VERSION 5.7 ;
BUSBITCHARS "[]" ;
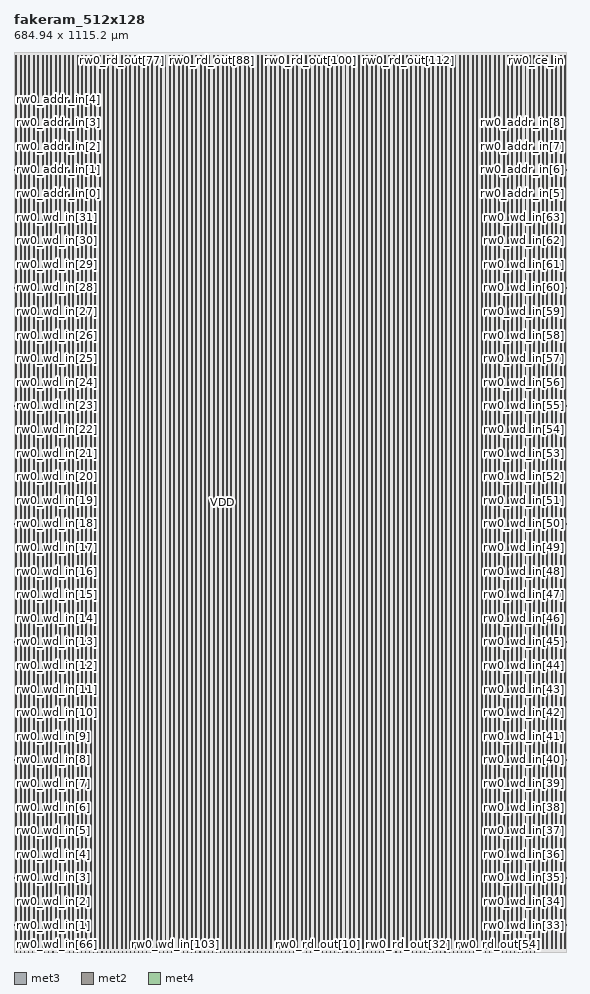
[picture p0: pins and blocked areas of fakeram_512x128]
MACRO fakeram_512x128
  FOREIGN fakeram_512x128 0 0 ;
  SYMMETRY X Y R90 ;
  SIZE 684.940 BY 1115.200 ;
  CLASS BLOCK ;
  PIN rw0_wd_in[0]
    DIRECTION INPUT ;
    USE SIGNAL ;
    SHAPE ABUTMENT ;
    PORT
      LAYER met3 ;
      RECT 0.000 3.930 0.900 4.230 ;
    END
  END rw0_wd_in[0]
  PIN rw0_wd_in[1]
    DIRECTION INPUT ;
    USE SIGNAL ;
    SHAPE ABUTMENT ;
    PORT
      LAYER met3 ;
      RECT 0.000 33.170 0.900 33.470 ;
    END
  END rw0_wd_in[1]
  PIN rw0_wd_in[2]
    DIRECTION INPUT ;
    USE SIGNAL ;
    SHAPE ABUTMENT ;
    PORT
      LAYER met3 ;
      RECT 0.000 62.410 0.900 62.710 ;
    END
  END rw0_wd_in[2]
  PIN rw0_wd_in[3]
    DIRECTION INPUT ;
    USE SIGNAL ;
    SHAPE ABUTMENT ;
    PORT
      LAYER met3 ;
      RECT 0.000 91.650 0.900 91.950 ;
    END
  END rw0_wd_in[3]
  PIN rw0_wd_in[4]
    DIRECTION INPUT ;
    USE SIGNAL ;
    SHAPE ABUTMENT ;
    PORT
      LAYER met3 ;
      RECT 0.000 120.890 0.900 121.190 ;
    END
  END rw0_wd_in[4]
  PIN rw0_wd_in[5]
    DIRECTION INPUT ;
    USE SIGNAL ;
    SHAPE ABUTMENT ;
    PORT
      LAYER met3 ;
      RECT 0.000 150.130 0.900 150.430 ;
    END
  END rw0_wd_in[5]
  PIN rw0_wd_in[6]
    DIRECTION INPUT ;
    USE SIGNAL ;
    SHAPE ABUTMENT ;
    PORT
      LAYER met3 ;
      RECT 0.000 179.370 0.900 179.670 ;
    END
  END rw0_wd_in[6]
  PIN rw0_wd_in[7]
    DIRECTION INPUT ;
    USE SIGNAL ;
    SHAPE ABUTMENT ;
    PORT
      LAYER met3 ;
      RECT 0.000 208.610 0.900 208.910 ;
    END
  END rw0_wd_in[7]
  PIN rw0_wd_in[8]
    DIRECTION INPUT ;
    USE SIGNAL ;
    SHAPE ABUTMENT ;
    PORT
      LAYER met3 ;
      RECT 0.000 237.850 0.900 238.150 ;
    END
  END rw0_wd_in[8]
  PIN rw0_wd_in[9]
    DIRECTION INPUT ;
    USE SIGNAL ;
    SHAPE ABUTMENT ;
    PORT
      LAYER met3 ;
      RECT 0.000 267.090 0.900 267.390 ;
    END
  END rw0_wd_in[9]
  PIN rw0_wd_in[10]
    DIRECTION INPUT ;
    USE SIGNAL ;
    SHAPE ABUTMENT ;
    PORT
      LAYER met3 ;
      RECT 0.000 296.330 0.900 296.630 ;
    END
  END rw0_wd_in[10]
  PIN rw0_wd_in[11]
    DIRECTION INPUT ;
    USE SIGNAL ;
    SHAPE ABUTMENT ;
    PORT
      LAYER met3 ;
      RECT 0.000 325.570 0.900 325.870 ;
    END
  END rw0_wd_in[11]
  PIN rw0_wd_in[12]
    DIRECTION INPUT ;
    USE SIGNAL ;
    SHAPE ABUTMENT ;
    PORT
      LAYER met3 ;
      RECT 0.000 354.810 0.900 355.110 ;
    END
  END rw0_wd_in[12]
  PIN rw0_wd_in[13]
    DIRECTION INPUT ;
    USE SIGNAL ;
    SHAPE ABUTMENT ;
    PORT
      LAYER met3 ;
      RECT 0.000 384.050 0.900 384.350 ;
    END
  END rw0_wd_in[13]
  PIN rw0_wd_in[14]
    DIRECTION INPUT ;
    USE SIGNAL ;
    SHAPE ABUTMENT ;
    PORT
      LAYER met3 ;
      RECT 0.000 413.290 0.900 413.590 ;
    END
  END rw0_wd_in[14]
  PIN rw0_wd_in[15]
    DIRECTION INPUT ;
    USE SIGNAL ;
    SHAPE ABUTMENT ;
    PORT
      LAYER met3 ;
      RECT 0.000 442.530 0.900 442.830 ;
    END
  END rw0_wd_in[15]
  PIN rw0_wd_in[16]
    DIRECTION INPUT ;
    USE SIGNAL ;
    SHAPE ABUTMENT ;
    PORT
      LAYER met3 ;
      RECT 0.000 471.770 0.900 472.070 ;
    END
  END rw0_wd_in[16]
  PIN rw0_wd_in[17]
    DIRECTION INPUT ;
    USE SIGNAL ;
    SHAPE ABUTMENT ;
    PORT
      LAYER met3 ;
      RECT 0.000 501.010 0.900 501.310 ;
    END
  END rw0_wd_in[17]
  PIN rw0_wd_in[18]
    DIRECTION INPUT ;
    USE SIGNAL ;
    SHAPE ABUTMENT ;
    PORT
      LAYER met3 ;
      RECT 0.000 530.250 0.900 530.550 ;
    END
  END rw0_wd_in[18]
  PIN rw0_wd_in[19]
    DIRECTION INPUT ;
    USE SIGNAL ;
    SHAPE ABUTMENT ;
    PORT
      LAYER met3 ;
      RECT 0.000 559.490 0.900 559.790 ;
    END
  END rw0_wd_in[19]
  PIN rw0_wd_in[20]
    DIRECTION INPUT ;
    USE SIGNAL ;
    SHAPE ABUTMENT ;
    PORT
      LAYER met3 ;
      RECT 0.000 588.730 0.900 589.030 ;
    END
  END rw0_wd_in[20]
  PIN rw0_wd_in[21]
    DIRECTION INPUT ;
    USE SIGNAL ;
    SHAPE ABUTMENT ;
    PORT
      LAYER met3 ;
      RECT 0.000 617.970 0.900 618.270 ;
    END
  END rw0_wd_in[21]
  PIN rw0_wd_in[22]
    DIRECTION INPUT ;
    USE SIGNAL ;
    SHAPE ABUTMENT ;
    PORT
      LAYER met3 ;
      RECT 0.000 647.210 0.900 647.510 ;
    END
  END rw0_wd_in[22]
  PIN rw0_wd_in[23]
    DIRECTION INPUT ;
    USE SIGNAL ;
    SHAPE ABUTMENT ;
    PORT
      LAYER met3 ;
      RECT 0.000 676.450 0.900 676.750 ;
    END
  END rw0_wd_in[23]
  PIN rw0_wd_in[24]
    DIRECTION INPUT ;
    USE SIGNAL ;
    SHAPE ABUTMENT ;
    PORT
      LAYER met3 ;
      RECT 0.000 705.690 0.900 705.990 ;
    END
  END rw0_wd_in[24]
  PIN rw0_wd_in[25]
    DIRECTION INPUT ;
    USE SIGNAL ;
    SHAPE ABUTMENT ;
    PORT
      LAYER met3 ;
      RECT 0.000 734.930 0.900 735.230 ;
    END
  END rw0_wd_in[25]
  PIN rw0_wd_in[26]
    DIRECTION INPUT ;
    USE SIGNAL ;
    SHAPE ABUTMENT ;
    PORT
      LAYER met3 ;
      RECT 0.000 764.170 0.900 764.470 ;
    END
  END rw0_wd_in[26]
  PIN rw0_wd_in[27]
    DIRECTION INPUT ;
    USE SIGNAL ;
    SHAPE ABUTMENT ;
    PORT
      LAYER met3 ;
      RECT 0.000 793.410 0.900 793.710 ;
    END
  END rw0_wd_in[27]
  PIN rw0_wd_in[28]
    DIRECTION INPUT ;
    USE SIGNAL ;
    SHAPE ABUTMENT ;
    PORT
      LAYER met3 ;
      RECT 0.000 822.650 0.900 822.950 ;
    END
  END rw0_wd_in[28]
  PIN rw0_wd_in[29]
    DIRECTION INPUT ;
    USE SIGNAL ;
    SHAPE ABUTMENT ;
    PORT
      LAYER met3 ;
      RECT 0.000 851.890 0.900 852.190 ;
    END
  END rw0_wd_in[29]
  PIN rw0_wd_in[30]
    DIRECTION INPUT ;
    USE SIGNAL ;
    SHAPE ABUTMENT ;
    PORT
      LAYER met3 ;
      RECT 0.000 881.130 0.900 881.430 ;
    END
  END rw0_wd_in[30]
  PIN rw0_wd_in[31]
    DIRECTION INPUT ;
    USE SIGNAL ;
    SHAPE ABUTMENT ;
    PORT
      LAYER met3 ;
      RECT 0.000 910.370 0.900 910.670 ;
    END
  END rw0_wd_in[31]
  PIN rw0_wd_in[32]
    DIRECTION INPUT ;
    USE SIGNAL ;
    SHAPE ABUTMENT ;
    PORT
      LAYER met3 ;
      RECT 684.040 3.930 684.940 4.230 ;
    END
  END rw0_wd_in[32]
  PIN rw0_wd_in[33]
    DIRECTION INPUT ;
    USE SIGNAL ;
    SHAPE ABUTMENT ;
    PORT
      LAYER met3 ;
      RECT 684.040 33.170 684.940 33.470 ;
    END
  END rw0_wd_in[33]
  PIN rw0_wd_in[34]
    DIRECTION INPUT ;
    USE SIGNAL ;
    SHAPE ABUTMENT ;
    PORT
      LAYER met3 ;
      RECT 684.040 62.410 684.940 62.710 ;
    END
  END rw0_wd_in[34]
  PIN rw0_wd_in[35]
    DIRECTION INPUT ;
    USE SIGNAL ;
    SHAPE ABUTMENT ;
    PORT
      LAYER met3 ;
      RECT 684.040 91.650 684.940 91.950 ;
    END
  END rw0_wd_in[35]
  PIN rw0_wd_in[36]
    DIRECTION INPUT ;
    USE SIGNAL ;
    SHAPE ABUTMENT ;
    PORT
      LAYER met3 ;
      RECT 684.040 120.890 684.940 121.190 ;
    END
  END rw0_wd_in[36]
  PIN rw0_wd_in[37]
    DIRECTION INPUT ;
    USE SIGNAL ;
    SHAPE ABUTMENT ;
    PORT
      LAYER met3 ;
      RECT 684.040 150.130 684.940 150.430 ;
    END
  END rw0_wd_in[37]
  PIN rw0_wd_in[38]
    DIRECTION INPUT ;
    USE SIGNAL ;
    SHAPE ABUTMENT ;
    PORT
      LAYER met3 ;
      RECT 684.040 179.370 684.940 179.670 ;
    END
  END rw0_wd_in[38]
  PIN rw0_wd_in[39]
    DIRECTION INPUT ;
    USE SIGNAL ;
    SHAPE ABUTMENT ;
    PORT
      LAYER met3 ;
      RECT 684.040 208.610 684.940 208.910 ;
    END
  END rw0_wd_in[39]
  PIN rw0_wd_in[40]
    DIRECTION INPUT ;
    USE SIGNAL ;
    SHAPE ABUTMENT ;
    PORT
      LAYER met3 ;
      RECT 684.040 237.850 684.940 238.150 ;
    END
  END rw0_wd_in[40]
  PIN rw0_wd_in[41]
    DIRECTION INPUT ;
    USE SIGNAL ;
    SHAPE ABUTMENT ;
    PORT
      LAYER met3 ;
      RECT 684.040 267.090 684.940 267.390 ;
    END
  END rw0_wd_in[41]
  PIN rw0_wd_in[42]
    DIRECTION INPUT ;
    USE SIGNAL ;
    SHAPE ABUTMENT ;
    PORT
      LAYER met3 ;
      RECT 684.040 296.330 684.940 296.630 ;
    END
  END rw0_wd_in[42]
  PIN rw0_wd_in[43]
    DIRECTION INPUT ;
    USE SIGNAL ;
    SHAPE ABUTMENT ;
    PORT
      LAYER met3 ;
      RECT 684.040 325.570 684.940 325.870 ;
    END
  END rw0_wd_in[43]
  PIN rw0_wd_in[44]
    DIRECTION INPUT ;
    USE SIGNAL ;
    SHAPE ABUTMENT ;
    PORT
      LAYER met3 ;
      RECT 684.040 354.810 684.940 355.110 ;
    END
  END rw0_wd_in[44]
  PIN rw0_wd_in[45]
    DIRECTION INPUT ;
    USE SIGNAL ;
    SHAPE ABUTMENT ;
    PORT
      LAYER met3 ;
      RECT 684.040 384.050 684.940 384.350 ;
    END
  END rw0_wd_in[45]
  PIN rw0_wd_in[46]
    DIRECTION INPUT ;
    USE SIGNAL ;
    SHAPE ABUTMENT ;
    PORT
      LAYER met3 ;
      RECT 684.040 413.290 684.940 413.590 ;
    END
  END rw0_wd_in[46]
  PIN rw0_wd_in[47]
    DIRECTION INPUT ;
    USE SIGNAL ;
    SHAPE ABUTMENT ;
    PORT
      LAYER met3 ;
      RECT 684.040 442.530 684.940 442.830 ;
    END
  END rw0_wd_in[47]
  PIN rw0_wd_in[48]
    DIRECTION INPUT ;
    USE SIGNAL ;
    SHAPE ABUTMENT ;
    PORT
      LAYER met3 ;
      RECT 684.040 471.770 684.940 472.070 ;
    END
  END rw0_wd_in[48]
  PIN rw0_wd_in[49]
    DIRECTION INPUT ;
    USE SIGNAL ;
    SHAPE ABUTMENT ;
    PORT
      LAYER met3 ;
      RECT 684.040 501.010 684.940 501.310 ;
    END
  END rw0_wd_in[49]
  PIN rw0_wd_in[50]
    DIRECTION INPUT ;
    USE SIGNAL ;
    SHAPE ABUTMENT ;
    PORT
      LAYER met3 ;
      RECT 684.040 530.250 684.940 530.550 ;
    END
  END rw0_wd_in[50]
  PIN rw0_wd_in[51]
    DIRECTION INPUT ;
    USE SIGNAL ;
    SHAPE ABUTMENT ;
    PORT
      LAYER met3 ;
      RECT 684.040 559.490 684.940 559.790 ;
    END
  END rw0_wd_in[51]
  PIN rw0_wd_in[52]
    DIRECTION INPUT ;
    USE SIGNAL ;
    SHAPE ABUTMENT ;
    PORT
      LAYER met3 ;
      RECT 684.040 588.730 684.940 589.030 ;
    END
  END rw0_wd_in[52]
  PIN rw0_wd_in[53]
    DIRECTION INPUT ;
    USE SIGNAL ;
    SHAPE ABUTMENT ;
    PORT
      LAYER met3 ;
      RECT 684.040 617.970 684.940 618.270 ;
    END
  END rw0_wd_in[53]
  PIN rw0_wd_in[54]
    DIRECTION INPUT ;
    USE SIGNAL ;
    SHAPE ABUTMENT ;
    PORT
      LAYER met3 ;
      RECT 684.040 647.210 684.940 647.510 ;
    END
  END rw0_wd_in[54]
  PIN rw0_wd_in[55]
    DIRECTION INPUT ;
    USE SIGNAL ;
    SHAPE ABUTMENT ;
    PORT
      LAYER met3 ;
      RECT 684.040 676.450 684.940 676.750 ;
    END
  END rw0_wd_in[55]
  PIN rw0_wd_in[56]
    DIRECTION INPUT ;
    USE SIGNAL ;
    SHAPE ABUTMENT ;
    PORT
      LAYER met3 ;
      RECT 684.040 705.690 684.940 705.990 ;
    END
  END rw0_wd_in[56]
  PIN rw0_wd_in[57]
    DIRECTION INPUT ;
    USE SIGNAL ;
    SHAPE ABUTMENT ;
    PORT
      LAYER met3 ;
      RECT 684.040 734.930 684.940 735.230 ;
    END
  END rw0_wd_in[57]
  PIN rw0_wd_in[58]
    DIRECTION INPUT ;
    USE SIGNAL ;
    SHAPE ABUTMENT ;
    PORT
      LAYER met3 ;
      RECT 684.040 764.170 684.940 764.470 ;
    END
  END rw0_wd_in[58]
  PIN rw0_wd_in[59]
    DIRECTION INPUT ;
    USE SIGNAL ;
    SHAPE ABUTMENT ;
    PORT
      LAYER met3 ;
      RECT 684.040 793.410 684.940 793.710 ;
    END
  END rw0_wd_in[59]
  PIN rw0_wd_in[60]
    DIRECTION INPUT ;
    USE SIGNAL ;
    SHAPE ABUTMENT ;
    PORT
      LAYER met3 ;
      RECT 684.040 822.650 684.940 822.950 ;
    END
  END rw0_wd_in[60]
  PIN rw0_wd_in[61]
    DIRECTION INPUT ;
    USE SIGNAL ;
    SHAPE ABUTMENT ;
    PORT
      LAYER met3 ;
      RECT 684.040 851.890 684.940 852.190 ;
    END
  END rw0_wd_in[61]
  PIN rw0_wd_in[62]
    DIRECTION INPUT ;
    USE SIGNAL ;
    SHAPE ABUTMENT ;
    PORT
      LAYER met3 ;
      RECT 684.040 881.130 684.940 881.430 ;
    END
  END rw0_wd_in[62]
  PIN rw0_wd_in[63]
    DIRECTION INPUT ;
    USE SIGNAL ;
    SHAPE ABUTMENT ;
    PORT
      LAYER met3 ;
      RECT 684.040 910.370 684.940 910.670 ;
    END
  END rw0_wd_in[63]
  PIN rw0_wd_in[64]
    DIRECTION INPUT ;
    USE SIGNAL ;
    SHAPE ABUTMENT ;
    PORT
      LAYER met2 ;
      RECT 2.690 0.000 2.830 0.420 ;
    END
  END rw0_wd_in[64]
  PIN rw0_wd_in[65]
    DIRECTION INPUT ;
    USE SIGNAL ;
    SHAPE ABUTMENT ;
    PORT
      LAYER met2 ;
      RECT 7.750 0.000 7.890 0.420 ;
    END
  END rw0_wd_in[65]
  PIN rw0_wd_in[66]
    DIRECTION INPUT ;
    USE SIGNAL ;
    SHAPE ABUTMENT ;
    PORT
      LAYER met2 ;
      RECT 12.810 0.000 12.950 0.420 ;
    END
  END rw0_wd_in[66]
  PIN rw0_wd_in[67]
    DIRECTION INPUT ;
    USE SIGNAL ;
    SHAPE ABUTMENT ;
    PORT
      LAYER met2 ;
      RECT 17.870 0.000 18.010 0.420 ;
    END
  END rw0_wd_in[67]
  PIN rw0_wd_in[68]
    DIRECTION INPUT ;
    USE SIGNAL ;
    SHAPE ABUTMENT ;
    PORT
      LAYER met2 ;
      RECT 22.930 0.000 23.070 0.420 ;
    END
  END rw0_wd_in[68]
  PIN rw0_wd_in[69]
    DIRECTION INPUT ;
    USE SIGNAL ;
    SHAPE ABUTMENT ;
    PORT
      LAYER met2 ;
      RECT 27.990 0.000 28.130 0.420 ;
    END
  END rw0_wd_in[69]
  PIN rw0_wd_in[70]
    DIRECTION INPUT ;
    USE SIGNAL ;
    SHAPE ABUTMENT ;
    PORT
      LAYER met2 ;
      RECT 33.050 0.000 33.190 0.420 ;
    END
  END rw0_wd_in[70]
  PIN rw0_wd_in[71]
    DIRECTION INPUT ;
    USE SIGNAL ;
    SHAPE ABUTMENT ;
    PORT
      LAYER met2 ;
      RECT 38.110 0.000 38.250 0.420 ;
    END
  END rw0_wd_in[71]
  PIN rw0_wd_in[72]
    DIRECTION INPUT ;
    USE SIGNAL ;
    SHAPE ABUTMENT ;
    PORT
      LAYER met2 ;
      RECT 43.170 0.000 43.310 0.420 ;
    END
  END rw0_wd_in[72]
  PIN rw0_wd_in[73]
    DIRECTION INPUT ;
    USE SIGNAL ;
    SHAPE ABUTMENT ;
    PORT
      LAYER met2 ;
      RECT 48.230 0.000 48.370 0.420 ;
    END
  END rw0_wd_in[73]
  PIN rw0_wd_in[74]
    DIRECTION INPUT ;
    USE SIGNAL ;
    SHAPE ABUTMENT ;
    PORT
      LAYER met2 ;
      RECT 53.290 0.000 53.430 0.420 ;
    END
  END rw0_wd_in[74]
  PIN rw0_wd_in[75]
    DIRECTION INPUT ;
    USE SIGNAL ;
    SHAPE ABUTMENT ;
    PORT
      LAYER met2 ;
      RECT 58.350 0.000 58.490 0.420 ;
    END
  END rw0_wd_in[75]
  PIN rw0_wd_in[76]
    DIRECTION INPUT ;
    USE SIGNAL ;
    SHAPE ABUTMENT ;
    PORT
      LAYER met2 ;
      RECT 63.410 0.000 63.550 0.420 ;
    END
  END rw0_wd_in[76]
  PIN rw0_wd_in[77]
    DIRECTION INPUT ;
    USE SIGNAL ;
    SHAPE ABUTMENT ;
    PORT
      LAYER met2 ;
      RECT 68.470 0.000 68.610 0.420 ;
    END
  END rw0_wd_in[77]
  PIN rw0_wd_in[78]
    DIRECTION INPUT ;
    USE SIGNAL ;
    SHAPE ABUTMENT ;
    PORT
      LAYER met2 ;
      RECT 73.530 0.000 73.670 0.420 ;
    END
  END rw0_wd_in[78]
  PIN rw0_wd_in[79]
    DIRECTION INPUT ;
    USE SIGNAL ;
    SHAPE ABUTMENT ;
    PORT
      LAYER met2 ;
      RECT 78.590 0.000 78.730 0.420 ;
    END
  END rw0_wd_in[79]
  PIN rw0_wd_in[80]
    DIRECTION INPUT ;
    USE SIGNAL ;
    SHAPE ABUTMENT ;
    PORT
      LAYER met2 ;
      RECT 83.650 0.000 83.790 0.420 ;
    END
  END rw0_wd_in[80]
  PIN rw0_wd_in[81]
    DIRECTION INPUT ;
    USE SIGNAL ;
    SHAPE ABUTMENT ;
    PORT
      LAYER met2 ;
      RECT 88.710 0.000 88.850 0.420 ;
    END
  END rw0_wd_in[81]
  PIN rw0_wd_in[82]
    DIRECTION INPUT ;
    USE SIGNAL ;
    SHAPE ABUTMENT ;
    PORT
      LAYER met2 ;
      RECT 93.770 0.000 93.910 0.420 ;
    END
  END rw0_wd_in[82]
  PIN rw0_wd_in[83]
    DIRECTION INPUT ;
    USE SIGNAL ;
    SHAPE ABUTMENT ;
    PORT
      LAYER met2 ;
      RECT 98.830 0.000 98.970 0.420 ;
    END
  END rw0_wd_in[83]
  PIN rw0_wd_in[84]
    DIRECTION INPUT ;
    USE SIGNAL ;
    SHAPE ABUTMENT ;
    PORT
      LAYER met2 ;
      RECT 103.890 0.000 104.030 0.420 ;
    END
  END rw0_wd_in[84]
  PIN rw0_wd_in[85]
    DIRECTION INPUT ;
    USE SIGNAL ;
    SHAPE ABUTMENT ;
    PORT
      LAYER met2 ;
      RECT 108.950 0.000 109.090 0.420 ;
    END
  END rw0_wd_in[85]
  PIN rw0_wd_in[86]
    DIRECTION INPUT ;
    USE SIGNAL ;
    SHAPE ABUTMENT ;
    PORT
      LAYER met2 ;
      RECT 114.010 0.000 114.150 0.420 ;
    END
  END rw0_wd_in[86]
  PIN rw0_wd_in[87]
    DIRECTION INPUT ;
    USE SIGNAL ;
    SHAPE ABUTMENT ;
    PORT
      LAYER met2 ;
      RECT 119.070 0.000 119.210 0.420 ;
    END
  END rw0_wd_in[87]
  PIN rw0_wd_in[88]
    DIRECTION INPUT ;
    USE SIGNAL ;
    SHAPE ABUTMENT ;
    PORT
      LAYER met2 ;
      RECT 124.130 0.000 124.270 0.420 ;
    END
  END rw0_wd_in[88]
  PIN rw0_wd_in[89]
    DIRECTION INPUT ;
    USE SIGNAL ;
    SHAPE ABUTMENT ;
    PORT
      LAYER met2 ;
      RECT 129.190 0.000 129.330 0.420 ;
    END
  END rw0_wd_in[89]
  PIN rw0_wd_in[90]
    DIRECTION INPUT ;
    USE SIGNAL ;
    SHAPE ABUTMENT ;
    PORT
      LAYER met2 ;
      RECT 134.250 0.000 134.390 0.420 ;
    END
  END rw0_wd_in[90]
  PIN rw0_wd_in[91]
    DIRECTION INPUT ;
    USE SIGNAL ;
    SHAPE ABUTMENT ;
    PORT
      LAYER met2 ;
      RECT 139.310 0.000 139.450 0.420 ;
    END
  END rw0_wd_in[91]
  PIN rw0_wd_in[92]
    DIRECTION INPUT ;
    USE SIGNAL ;
    SHAPE ABUTMENT ;
    PORT
      LAYER met2 ;
      RECT 144.370 0.000 144.510 0.420 ;
    END
  END rw0_wd_in[92]
  PIN rw0_wd_in[93]
    DIRECTION INPUT ;
    USE SIGNAL ;
    SHAPE ABUTMENT ;
    PORT
      LAYER met2 ;
      RECT 149.430 0.000 149.570 0.420 ;
    END
  END rw0_wd_in[93]
  PIN rw0_wd_in[94]
    DIRECTION INPUT ;
    USE SIGNAL ;
    SHAPE ABUTMENT ;
    PORT
      LAYER met2 ;
      RECT 154.490 0.000 154.630 0.420 ;
    END
  END rw0_wd_in[94]
  PIN rw0_wd_in[95]
    DIRECTION INPUT ;
    USE SIGNAL ;
    SHAPE ABUTMENT ;
    PORT
      LAYER met2 ;
      RECT 159.550 0.000 159.690 0.420 ;
    END
  END rw0_wd_in[95]
  PIN rw0_wd_in[96]
    DIRECTION INPUT ;
    USE SIGNAL ;
    SHAPE ABUTMENT ;
    PORT
      LAYER met2 ;
      RECT 164.610 0.000 164.750 0.420 ;
    END
  END rw0_wd_in[96]
  PIN rw0_wd_in[97]
    DIRECTION INPUT ;
    USE SIGNAL ;
    SHAPE ABUTMENT ;
    PORT
      LAYER met2 ;
      RECT 169.670 0.000 169.810 0.420 ;
    END
  END rw0_wd_in[97]
  PIN rw0_wd_in[98]
    DIRECTION INPUT ;
    USE SIGNAL ;
    SHAPE ABUTMENT ;
    PORT
      LAYER met2 ;
      RECT 174.730 0.000 174.870 0.420 ;
    END
  END rw0_wd_in[98]
  PIN rw0_wd_in[99]
    DIRECTION INPUT ;
    USE SIGNAL ;
    SHAPE ABUTMENT ;
    PORT
      LAYER met2 ;
      RECT 179.790 0.000 179.930 0.420 ;
    END
  END rw0_wd_in[99]
  PIN rw0_wd_in[100]
    DIRECTION INPUT ;
    USE SIGNAL ;
    SHAPE ABUTMENT ;
    PORT
      LAYER met2 ;
      RECT 184.850 0.000 184.990 0.420 ;
    END
  END rw0_wd_in[100]
  PIN rw0_wd_in[101]
    DIRECTION INPUT ;
    USE SIGNAL ;
    SHAPE ABUTMENT ;
    PORT
      LAYER met2 ;
      RECT 189.910 0.000 190.050 0.420 ;
    END
  END rw0_wd_in[101]
  PIN rw0_wd_in[102]
    DIRECTION INPUT ;
    USE SIGNAL ;
    SHAPE ABUTMENT ;
    PORT
      LAYER met2 ;
      RECT 194.970 0.000 195.110 0.420 ;
    END
  END rw0_wd_in[102]
  PIN rw0_wd_in[103]
    DIRECTION INPUT ;
    USE SIGNAL ;
    SHAPE ABUTMENT ;
    PORT
      LAYER met2 ;
      RECT 200.030 0.000 200.170 0.420 ;
    END
  END rw0_wd_in[103]
  PIN rw0_wd_in[104]
    DIRECTION INPUT ;
    USE SIGNAL ;
    SHAPE ABUTMENT ;
    PORT
      LAYER met2 ;
      RECT 205.090 0.000 205.230 0.420 ;
    END
  END rw0_wd_in[104]
  PIN rw0_wd_in[105]
    DIRECTION INPUT ;
    USE SIGNAL ;
    SHAPE ABUTMENT ;
    PORT
      LAYER met2 ;
      RECT 210.150 0.000 210.290 0.420 ;
    END
  END rw0_wd_in[105]
  PIN rw0_wd_in[106]
    DIRECTION INPUT ;
    USE SIGNAL ;
    SHAPE ABUTMENT ;
    PORT
      LAYER met2 ;
      RECT 215.210 0.000 215.350 0.420 ;
    END
  END rw0_wd_in[106]
  PIN rw0_wd_in[107]
    DIRECTION INPUT ;
    USE SIGNAL ;
    SHAPE ABUTMENT ;
    PORT
      LAYER met2 ;
      RECT 220.270 0.000 220.410 0.420 ;
    END
  END rw0_wd_in[107]
  PIN rw0_wd_in[108]
    DIRECTION INPUT ;
    USE SIGNAL ;
    SHAPE ABUTMENT ;
    PORT
      LAYER met2 ;
      RECT 225.330 0.000 225.470 0.420 ;
    END
  END rw0_wd_in[108]
  PIN rw0_wd_in[109]
    DIRECTION INPUT ;
    USE SIGNAL ;
    SHAPE ABUTMENT ;
    PORT
      LAYER met2 ;
      RECT 230.390 0.000 230.530 0.420 ;
    END
  END rw0_wd_in[109]
  PIN rw0_wd_in[110]
    DIRECTION INPUT ;
    USE SIGNAL ;
    SHAPE ABUTMENT ;
    PORT
      LAYER met2 ;
      RECT 235.450 0.000 235.590 0.420 ;
    END
  END rw0_wd_in[110]
  PIN rw0_wd_in[111]
    DIRECTION INPUT ;
    USE SIGNAL ;
    SHAPE ABUTMENT ;
    PORT
      LAYER met2 ;
      RECT 240.510 0.000 240.650 0.420 ;
    END
  END rw0_wd_in[111]
  PIN rw0_wd_in[112]
    DIRECTION INPUT ;
    USE SIGNAL ;
    SHAPE ABUTMENT ;
    PORT
      LAYER met2 ;
      RECT 245.570 0.000 245.710 0.420 ;
    END
  END rw0_wd_in[112]
  PIN rw0_wd_in[113]
    DIRECTION INPUT ;
    USE SIGNAL ;
    SHAPE ABUTMENT ;
    PORT
      LAYER met2 ;
      RECT 250.630 0.000 250.770 0.420 ;
    END
  END rw0_wd_in[113]
  PIN rw0_wd_in[114]
    DIRECTION INPUT ;
    USE SIGNAL ;
    SHAPE ABUTMENT ;
    PORT
      LAYER met2 ;
      RECT 255.690 0.000 255.830 0.420 ;
    END
  END rw0_wd_in[114]
  PIN rw0_wd_in[115]
    DIRECTION INPUT ;
    USE SIGNAL ;
    SHAPE ABUTMENT ;
    PORT
      LAYER met2 ;
      RECT 260.750 0.000 260.890 0.420 ;
    END
  END rw0_wd_in[115]
  PIN rw0_wd_in[116]
    DIRECTION INPUT ;
    USE SIGNAL ;
    SHAPE ABUTMENT ;
    PORT
      LAYER met2 ;
      RECT 265.810 0.000 265.950 0.420 ;
    END
  END rw0_wd_in[116]
  PIN rw0_wd_in[117]
    DIRECTION INPUT ;
    USE SIGNAL ;
    SHAPE ABUTMENT ;
    PORT
      LAYER met2 ;
      RECT 270.870 0.000 271.010 0.420 ;
    END
  END rw0_wd_in[117]
  PIN rw0_wd_in[118]
    DIRECTION INPUT ;
    USE SIGNAL ;
    SHAPE ABUTMENT ;
    PORT
      LAYER met2 ;
      RECT 275.930 0.000 276.070 0.420 ;
    END
  END rw0_wd_in[118]
  PIN rw0_wd_in[119]
    DIRECTION INPUT ;
    USE SIGNAL ;
    SHAPE ABUTMENT ;
    PORT
      LAYER met2 ;
      RECT 280.990 0.000 281.130 0.420 ;
    END
  END rw0_wd_in[119]
  PIN rw0_wd_in[120]
    DIRECTION INPUT ;
    USE SIGNAL ;
    SHAPE ABUTMENT ;
    PORT
      LAYER met2 ;
      RECT 286.050 0.000 286.190 0.420 ;
    END
  END rw0_wd_in[120]
  PIN rw0_wd_in[121]
    DIRECTION INPUT ;
    USE SIGNAL ;
    SHAPE ABUTMENT ;
    PORT
      LAYER met2 ;
      RECT 291.110 0.000 291.250 0.420 ;
    END
  END rw0_wd_in[121]
  PIN rw0_wd_in[122]
    DIRECTION INPUT ;
    USE SIGNAL ;
    SHAPE ABUTMENT ;
    PORT
      LAYER met2 ;
      RECT 296.170 0.000 296.310 0.420 ;
    END
  END rw0_wd_in[122]
  PIN rw0_wd_in[123]
    DIRECTION INPUT ;
    USE SIGNAL ;
    SHAPE ABUTMENT ;
    PORT
      LAYER met2 ;
      RECT 301.230 0.000 301.370 0.420 ;
    END
  END rw0_wd_in[123]
  PIN rw0_wd_in[124]
    DIRECTION INPUT ;
    USE SIGNAL ;
    SHAPE ABUTMENT ;
    PORT
      LAYER met2 ;
      RECT 306.290 0.000 306.430 0.420 ;
    END
  END rw0_wd_in[124]
  PIN rw0_wd_in[125]
    DIRECTION INPUT ;
    USE SIGNAL ;
    SHAPE ABUTMENT ;
    PORT
      LAYER met2 ;
      RECT 311.350 0.000 311.490 0.420 ;
    END
  END rw0_wd_in[125]
  PIN rw0_wd_in[126]
    DIRECTION INPUT ;
    USE SIGNAL ;
    SHAPE ABUTMENT ;
    PORT
      LAYER met2 ;
      RECT 316.410 0.000 316.550 0.420 ;
    END
  END rw0_wd_in[126]
  PIN rw0_wd_in[127]
    DIRECTION INPUT ;
    USE SIGNAL ;
    SHAPE ABUTMENT ;
    PORT
      LAYER met2 ;
      RECT 321.470 0.000 321.610 0.420 ;
    END
  END rw0_wd_in[127]
  PIN rw0_rd_out[0]
    DIRECTION OUTPUT ;
    USE SIGNAL ;
    SHAPE ABUTMENT ;
    PORT
      LAYER met2 ;
      RECT 326.530 0.000 326.670 0.420 ;
    END
  END rw0_rd_out[0]
  PIN rw0_rd_out[1]
    DIRECTION OUTPUT ;
    USE SIGNAL ;
    SHAPE ABUTMENT ;
    PORT
      LAYER met2 ;
      RECT 331.590 0.000 331.730 0.420 ;
    END
  END rw0_rd_out[1]
  PIN rw0_rd_out[2]
    DIRECTION OUTPUT ;
    USE SIGNAL ;
    SHAPE ABUTMENT ;
    PORT
      LAYER met2 ;
      RECT 336.650 0.000 336.790 0.420 ;
    END
  END rw0_rd_out[2]
  PIN rw0_rd_out[3]
    DIRECTION OUTPUT ;
    USE SIGNAL ;
    SHAPE ABUTMENT ;
    PORT
      LAYER met2 ;
      RECT 341.710 0.000 341.850 0.420 ;
    END
  END rw0_rd_out[3]
  PIN rw0_rd_out[4]
    DIRECTION OUTPUT ;
    USE SIGNAL ;
    SHAPE ABUTMENT ;
    PORT
      LAYER met2 ;
      RECT 346.770 0.000 346.910 0.420 ;
    END
  END rw0_rd_out[4]
  PIN rw0_rd_out[5]
    DIRECTION OUTPUT ;
    USE SIGNAL ;
    SHAPE ABUTMENT ;
    PORT
      LAYER met2 ;
      RECT 351.830 0.000 351.970 0.420 ;
    END
  END rw0_rd_out[5]
  PIN rw0_rd_out[6]
    DIRECTION OUTPUT ;
    USE SIGNAL ;
    SHAPE ABUTMENT ;
    PORT
      LAYER met2 ;
      RECT 356.890 0.000 357.030 0.420 ;
    END
  END rw0_rd_out[6]
  PIN rw0_rd_out[7]
    DIRECTION OUTPUT ;
    USE SIGNAL ;
    SHAPE ABUTMENT ;
    PORT
      LAYER met2 ;
      RECT 361.950 0.000 362.090 0.420 ;
    END
  END rw0_rd_out[7]
  PIN rw0_rd_out[8]
    DIRECTION OUTPUT ;
    USE SIGNAL ;
    SHAPE ABUTMENT ;
    PORT
      LAYER met2 ;
      RECT 367.010 0.000 367.150 0.420 ;
    END
  END rw0_rd_out[8]
  PIN rw0_rd_out[9]
    DIRECTION OUTPUT ;
    USE SIGNAL ;
    SHAPE ABUTMENT ;
    PORT
      LAYER met2 ;
      RECT 372.070 0.000 372.210 0.420 ;
    END
  END rw0_rd_out[9]
  PIN rw0_rd_out[10]
    DIRECTION OUTPUT ;
    USE SIGNAL ;
    SHAPE ABUTMENT ;
    PORT
      LAYER met2 ;
      RECT 377.130 0.000 377.270 0.420 ;
    END
  END rw0_rd_out[10]
  PIN rw0_rd_out[11]
    DIRECTION OUTPUT ;
    USE SIGNAL ;
    SHAPE ABUTMENT ;
    PORT
      LAYER met2 ;
      RECT 382.190 0.000 382.330 0.420 ;
    END
  END rw0_rd_out[11]
  PIN rw0_rd_out[12]
    DIRECTION OUTPUT ;
    USE SIGNAL ;
    SHAPE ABUTMENT ;
    PORT
      LAYER met2 ;
      RECT 387.250 0.000 387.390 0.420 ;
    END
  END rw0_rd_out[12]
  PIN rw0_rd_out[13]
    DIRECTION OUTPUT ;
    USE SIGNAL ;
    SHAPE ABUTMENT ;
    PORT
      LAYER met2 ;
      RECT 392.310 0.000 392.450 0.420 ;
    END
  END rw0_rd_out[13]
  PIN rw0_rd_out[14]
    DIRECTION OUTPUT ;
    USE SIGNAL ;
    SHAPE ABUTMENT ;
    PORT
      LAYER met2 ;
      RECT 397.370 0.000 397.510 0.420 ;
    END
  END rw0_rd_out[14]
  PIN rw0_rd_out[15]
    DIRECTION OUTPUT ;
    USE SIGNAL ;
    SHAPE ABUTMENT ;
    PORT
      LAYER met2 ;
      RECT 402.430 0.000 402.570 0.420 ;
    END
  END rw0_rd_out[15]
  PIN rw0_rd_out[16]
    DIRECTION OUTPUT ;
    USE SIGNAL ;
    SHAPE ABUTMENT ;
    PORT
      LAYER met2 ;
      RECT 407.490 0.000 407.630 0.420 ;
    END
  END rw0_rd_out[16]
  PIN rw0_rd_out[17]
    DIRECTION OUTPUT ;
    USE SIGNAL ;
    SHAPE ABUTMENT ;
    PORT
      LAYER met2 ;
      RECT 412.550 0.000 412.690 0.420 ;
    END
  END rw0_rd_out[17]
  PIN rw0_rd_out[18]
    DIRECTION OUTPUT ;
    USE SIGNAL ;
    SHAPE ABUTMENT ;
    PORT
      LAYER met2 ;
      RECT 417.610 0.000 417.750 0.420 ;
    END
  END rw0_rd_out[18]
  PIN rw0_rd_out[19]
    DIRECTION OUTPUT ;
    USE SIGNAL ;
    SHAPE ABUTMENT ;
    PORT
      LAYER met2 ;
      RECT 422.670 0.000 422.810 0.420 ;
    END
  END rw0_rd_out[19]
  PIN rw0_rd_out[20]
    DIRECTION OUTPUT ;
    USE SIGNAL ;
    SHAPE ABUTMENT ;
    PORT
      LAYER met2 ;
      RECT 427.730 0.000 427.870 0.420 ;
    END
  END rw0_rd_out[20]
  PIN rw0_rd_out[21]
    DIRECTION OUTPUT ;
    USE SIGNAL ;
    SHAPE ABUTMENT ;
    PORT
      LAYER met2 ;
      RECT 432.790 0.000 432.930 0.420 ;
    END
  END rw0_rd_out[21]
  PIN rw0_rd_out[22]
    DIRECTION OUTPUT ;
    USE SIGNAL ;
    SHAPE ABUTMENT ;
    PORT
      LAYER met2 ;
      RECT 437.850 0.000 437.990 0.420 ;
    END
  END rw0_rd_out[22]
  PIN rw0_rd_out[23]
    DIRECTION OUTPUT ;
    USE SIGNAL ;
    SHAPE ABUTMENT ;
    PORT
      LAYER met2 ;
      RECT 442.910 0.000 443.050 0.420 ;
    END
  END rw0_rd_out[23]
  PIN rw0_rd_out[24]
    DIRECTION OUTPUT ;
    USE SIGNAL ;
    SHAPE ABUTMENT ;
    PORT
      LAYER met2 ;
      RECT 447.970 0.000 448.110 0.420 ;
    END
  END rw0_rd_out[24]
  PIN rw0_rd_out[25]
    DIRECTION OUTPUT ;
    USE SIGNAL ;
    SHAPE ABUTMENT ;
    PORT
      LAYER met2 ;
      RECT 453.030 0.000 453.170 0.420 ;
    END
  END rw0_rd_out[25]
  PIN rw0_rd_out[26]
    DIRECTION OUTPUT ;
    USE SIGNAL ;
    SHAPE ABUTMENT ;
    PORT
      LAYER met2 ;
      RECT 458.090 0.000 458.230 0.420 ;
    END
  END rw0_rd_out[26]
  PIN rw0_rd_out[27]
    DIRECTION OUTPUT ;
    USE SIGNAL ;
    SHAPE ABUTMENT ;
    PORT
      LAYER met2 ;
      RECT 463.150 0.000 463.290 0.420 ;
    END
  END rw0_rd_out[27]
  PIN rw0_rd_out[28]
    DIRECTION OUTPUT ;
    USE SIGNAL ;
    SHAPE ABUTMENT ;
    PORT
      LAYER met2 ;
      RECT 468.210 0.000 468.350 0.420 ;
    END
  END rw0_rd_out[28]
  PIN rw0_rd_out[29]
    DIRECTION OUTPUT ;
    USE SIGNAL ;
    SHAPE ABUTMENT ;
    PORT
      LAYER met2 ;
      RECT 473.270 0.000 473.410 0.420 ;
    END
  END rw0_rd_out[29]
  PIN rw0_rd_out[30]
    DIRECTION OUTPUT ;
    USE SIGNAL ;
    SHAPE ABUTMENT ;
    PORT
      LAYER met2 ;
      RECT 478.330 0.000 478.470 0.420 ;
    END
  END rw0_rd_out[30]
  PIN rw0_rd_out[31]
    DIRECTION OUTPUT ;
    USE SIGNAL ;
    SHAPE ABUTMENT ;
    PORT
      LAYER met2 ;
      RECT 483.390 0.000 483.530 0.420 ;
    END
  END rw0_rd_out[31]
  PIN rw0_rd_out[32]
    DIRECTION OUTPUT ;
    USE SIGNAL ;
    SHAPE ABUTMENT ;
    PORT
      LAYER met2 ;
      RECT 488.450 0.000 488.590 0.420 ;
    END
  END rw0_rd_out[32]
  PIN rw0_rd_out[33]
    DIRECTION OUTPUT ;
    USE SIGNAL ;
    SHAPE ABUTMENT ;
    PORT
      LAYER met2 ;
      RECT 493.510 0.000 493.650 0.420 ;
    END
  END rw0_rd_out[33]
  PIN rw0_rd_out[34]
    DIRECTION OUTPUT ;
    USE SIGNAL ;
    SHAPE ABUTMENT ;
    PORT
      LAYER met2 ;
      RECT 498.570 0.000 498.710 0.420 ;
    END
  END rw0_rd_out[34]
  PIN rw0_rd_out[35]
    DIRECTION OUTPUT ;
    USE SIGNAL ;
    SHAPE ABUTMENT ;
    PORT
      LAYER met2 ;
      RECT 503.630 0.000 503.770 0.420 ;
    END
  END rw0_rd_out[35]
  PIN rw0_rd_out[36]
    DIRECTION OUTPUT ;
    USE SIGNAL ;
    SHAPE ABUTMENT ;
    PORT
      LAYER met2 ;
      RECT 508.690 0.000 508.830 0.420 ;
    END
  END rw0_rd_out[36]
  PIN rw0_rd_out[37]
    DIRECTION OUTPUT ;
    USE SIGNAL ;
    SHAPE ABUTMENT ;
    PORT
      LAYER met2 ;
      RECT 513.750 0.000 513.890 0.420 ;
    END
  END rw0_rd_out[37]
  PIN rw0_rd_out[38]
    DIRECTION OUTPUT ;
    USE SIGNAL ;
    SHAPE ABUTMENT ;
    PORT
      LAYER met2 ;
      RECT 518.810 0.000 518.950 0.420 ;
    END
  END rw0_rd_out[38]
  PIN rw0_rd_out[39]
    DIRECTION OUTPUT ;
    USE SIGNAL ;
    SHAPE ABUTMENT ;
    PORT
      LAYER met2 ;
      RECT 523.870 0.000 524.010 0.420 ;
    END
  END rw0_rd_out[39]
  PIN rw0_rd_out[40]
    DIRECTION OUTPUT ;
    USE SIGNAL ;
    SHAPE ABUTMENT ;
    PORT
      LAYER met2 ;
      RECT 528.930 0.000 529.070 0.420 ;
    END
  END rw0_rd_out[40]
  PIN rw0_rd_out[41]
    DIRECTION OUTPUT ;
    USE SIGNAL ;
    SHAPE ABUTMENT ;
    PORT
      LAYER met2 ;
      RECT 533.990 0.000 534.130 0.420 ;
    END
  END rw0_rd_out[41]
  PIN rw0_rd_out[42]
    DIRECTION OUTPUT ;
    USE SIGNAL ;
    SHAPE ABUTMENT ;
    PORT
      LAYER met2 ;
      RECT 539.050 0.000 539.190 0.420 ;
    END
  END rw0_rd_out[42]
  PIN rw0_rd_out[43]
    DIRECTION OUTPUT ;
    USE SIGNAL ;
    SHAPE ABUTMENT ;
    PORT
      LAYER met2 ;
      RECT 544.110 0.000 544.250 0.420 ;
    END
  END rw0_rd_out[43]
  PIN rw0_rd_out[44]
    DIRECTION OUTPUT ;
    USE SIGNAL ;
    SHAPE ABUTMENT ;
    PORT
      LAYER met2 ;
      RECT 549.170 0.000 549.310 0.420 ;
    END
  END rw0_rd_out[44]
  PIN rw0_rd_out[45]
    DIRECTION OUTPUT ;
    USE SIGNAL ;
    SHAPE ABUTMENT ;
    PORT
      LAYER met2 ;
      RECT 554.230 0.000 554.370 0.420 ;
    END
  END rw0_rd_out[45]
  PIN rw0_rd_out[46]
    DIRECTION OUTPUT ;
    USE SIGNAL ;
    SHAPE ABUTMENT ;
    PORT
      LAYER met2 ;
      RECT 559.290 0.000 559.430 0.420 ;
    END
  END rw0_rd_out[46]
  PIN rw0_rd_out[47]
    DIRECTION OUTPUT ;
    USE SIGNAL ;
    SHAPE ABUTMENT ;
    PORT
      LAYER met2 ;
      RECT 564.350 0.000 564.490 0.420 ;
    END
  END rw0_rd_out[47]
  PIN rw0_rd_out[48]
    DIRECTION OUTPUT ;
    USE SIGNAL ;
    SHAPE ABUTMENT ;
    PORT
      LAYER met2 ;
      RECT 569.410 0.000 569.550 0.420 ;
    END
  END rw0_rd_out[48]
  PIN rw0_rd_out[49]
    DIRECTION OUTPUT ;
    USE SIGNAL ;
    SHAPE ABUTMENT ;
    PORT
      LAYER met2 ;
      RECT 574.470 0.000 574.610 0.420 ;
    END
  END rw0_rd_out[49]
  PIN rw0_rd_out[50]
    DIRECTION OUTPUT ;
    USE SIGNAL ;
    SHAPE ABUTMENT ;
    PORT
      LAYER met2 ;
      RECT 579.530 0.000 579.670 0.420 ;
    END
  END rw0_rd_out[50]
  PIN rw0_rd_out[51]
    DIRECTION OUTPUT ;
    USE SIGNAL ;
    SHAPE ABUTMENT ;
    PORT
      LAYER met2 ;
      RECT 584.590 0.000 584.730 0.420 ;
    END
  END rw0_rd_out[51]
  PIN rw0_rd_out[52]
    DIRECTION OUTPUT ;
    USE SIGNAL ;
    SHAPE ABUTMENT ;
    PORT
      LAYER met2 ;
      RECT 589.650 0.000 589.790 0.420 ;
    END
  END rw0_rd_out[52]
  PIN rw0_rd_out[53]
    DIRECTION OUTPUT ;
    USE SIGNAL ;
    SHAPE ABUTMENT ;
    PORT
      LAYER met2 ;
      RECT 594.710 0.000 594.850 0.420 ;
    END
  END rw0_rd_out[53]
  PIN rw0_rd_out[54]
    DIRECTION OUTPUT ;
    USE SIGNAL ;
    SHAPE ABUTMENT ;
    PORT
      LAYER met2 ;
      RECT 599.770 0.000 599.910 0.420 ;
    END
  END rw0_rd_out[54]
  PIN rw0_rd_out[55]
    DIRECTION OUTPUT ;
    USE SIGNAL ;
    SHAPE ABUTMENT ;
    PORT
      LAYER met2 ;
      RECT 604.830 0.000 604.970 0.420 ;
    END
  END rw0_rd_out[55]
  PIN rw0_rd_out[56]
    DIRECTION OUTPUT ;
    USE SIGNAL ;
    SHAPE ABUTMENT ;
    PORT
      LAYER met2 ;
      RECT 609.890 0.000 610.030 0.420 ;
    END
  END rw0_rd_out[56]
  PIN rw0_rd_out[57]
    DIRECTION OUTPUT ;
    USE SIGNAL ;
    SHAPE ABUTMENT ;
    PORT
      LAYER met2 ;
      RECT 614.950 0.000 615.090 0.420 ;
    END
  END rw0_rd_out[57]
  PIN rw0_rd_out[58]
    DIRECTION OUTPUT ;
    USE SIGNAL ;
    SHAPE ABUTMENT ;
    PORT
      LAYER met2 ;
      RECT 620.010 0.000 620.150 0.420 ;
    END
  END rw0_rd_out[58]
  PIN rw0_rd_out[59]
    DIRECTION OUTPUT ;
    USE SIGNAL ;
    SHAPE ABUTMENT ;
    PORT
      LAYER met2 ;
      RECT 625.070 0.000 625.210 0.420 ;
    END
  END rw0_rd_out[59]
  PIN rw0_rd_out[60]
    DIRECTION OUTPUT ;
    USE SIGNAL ;
    SHAPE ABUTMENT ;
    PORT
      LAYER met2 ;
      RECT 630.130 0.000 630.270 0.420 ;
    END
  END rw0_rd_out[60]
  PIN rw0_rd_out[61]
    DIRECTION OUTPUT ;
    USE SIGNAL ;
    SHAPE ABUTMENT ;
    PORT
      LAYER met2 ;
      RECT 635.190 0.000 635.330 0.420 ;
    END
  END rw0_rd_out[61]
  PIN rw0_rd_out[62]
    DIRECTION OUTPUT ;
    USE SIGNAL ;
    SHAPE ABUTMENT ;
    PORT
      LAYER met2 ;
      RECT 640.250 0.000 640.390 0.420 ;
    END
  END rw0_rd_out[62]
  PIN rw0_rd_out[63]
    DIRECTION OUTPUT ;
    USE SIGNAL ;
    SHAPE ABUTMENT ;
    PORT
      LAYER met2 ;
      RECT 645.310 0.000 645.450 0.420 ;
    END
  END rw0_rd_out[63]
  PIN rw0_rd_out[64]
    DIRECTION OUTPUT ;
    USE SIGNAL ;
    SHAPE ABUTMENT ;
    PORT
      LAYER met2 ;
      RECT 2.690 1114.780 2.830 1115.200 ;
    END
  END rw0_rd_out[64]
  PIN rw0_rd_out[65]
    DIRECTION OUTPUT ;
    USE SIGNAL ;
    SHAPE ABUTMENT ;
    PORT
      LAYER met2 ;
      RECT 12.810 1114.780 12.950 1115.200 ;
    END
  END rw0_rd_out[65]
  PIN rw0_rd_out[66]
    DIRECTION OUTPUT ;
    USE SIGNAL ;
    SHAPE ABUTMENT ;
    PORT
      LAYER met2 ;
      RECT 22.930 1114.780 23.070 1115.200 ;
    END
  END rw0_rd_out[66]
  PIN rw0_rd_out[67]
    DIRECTION OUTPUT ;
    USE SIGNAL ;
    SHAPE ABUTMENT ;
    PORT
      LAYER met2 ;
      RECT 33.050 1114.780 33.190 1115.200 ;
    END
  END rw0_rd_out[67]
  PIN rw0_rd_out[68]
    DIRECTION OUTPUT ;
    USE SIGNAL ;
    SHAPE ABUTMENT ;
    PORT
      LAYER met2 ;
      RECT 43.170 1114.780 43.310 1115.200 ;
    END
  END rw0_rd_out[68]
  PIN rw0_rd_out[69]
    DIRECTION OUTPUT ;
    USE SIGNAL ;
    SHAPE ABUTMENT ;
    PORT
      LAYER met2 ;
      RECT 53.290 1114.780 53.430 1115.200 ;
    END
  END rw0_rd_out[69]
  PIN rw0_rd_out[70]
    DIRECTION OUTPUT ;
    USE SIGNAL ;
    SHAPE ABUTMENT ;
    PORT
      LAYER met2 ;
      RECT 63.410 1114.780 63.550 1115.200 ;
    END
  END rw0_rd_out[70]
  PIN rw0_rd_out[71]
    DIRECTION OUTPUT ;
    USE SIGNAL ;
    SHAPE ABUTMENT ;
    PORT
      LAYER met2 ;
      RECT 73.530 1114.780 73.670 1115.200 ;
    END
  END rw0_rd_out[71]
  PIN rw0_rd_out[72]
    DIRECTION OUTPUT ;
    USE SIGNAL ;
    SHAPE ABUTMENT ;
    PORT
      LAYER met2 ;
      RECT 83.650 1114.780 83.790 1115.200 ;
    END
  END rw0_rd_out[72]
  PIN rw0_rd_out[73]
    DIRECTION OUTPUT ;
    USE SIGNAL ;
    SHAPE ABUTMENT ;
    PORT
      LAYER met2 ;
      RECT 93.770 1114.780 93.910 1115.200 ;
    END
  END rw0_rd_out[73]
  PIN rw0_rd_out[74]
    DIRECTION OUTPUT ;
    USE SIGNAL ;
    SHAPE ABUTMENT ;
    PORT
      LAYER met2 ;
      RECT 103.890 1114.780 104.030 1115.200 ;
    END
  END rw0_rd_out[74]
  PIN rw0_rd_out[75]
    DIRECTION OUTPUT ;
    USE SIGNAL ;
    SHAPE ABUTMENT ;
    PORT
      LAYER met2 ;
      RECT 114.010 1114.780 114.150 1115.200 ;
    END
  END rw0_rd_out[75]
  PIN rw0_rd_out[76]
    DIRECTION OUTPUT ;
    USE SIGNAL ;
    SHAPE ABUTMENT ;
    PORT
      LAYER met2 ;
      RECT 124.130 1114.780 124.270 1115.200 ;
    END
  END rw0_rd_out[76]
  PIN rw0_rd_out[77]
    DIRECTION OUTPUT ;
    USE SIGNAL ;
    SHAPE ABUTMENT ;
    PORT
      LAYER met2 ;
      RECT 134.250 1114.780 134.390 1115.200 ;
    END
  END rw0_rd_out[77]
  PIN rw0_rd_out[78]
    DIRECTION OUTPUT ;
    USE SIGNAL ;
    SHAPE ABUTMENT ;
    PORT
      LAYER met2 ;
      RECT 144.370 1114.780 144.510 1115.200 ;
    END
  END rw0_rd_out[78]
  PIN rw0_rd_out[79]
    DIRECTION OUTPUT ;
    USE SIGNAL ;
    SHAPE ABUTMENT ;
    PORT
      LAYER met2 ;
      RECT 154.490 1114.780 154.630 1115.200 ;
    END
  END rw0_rd_out[79]
  PIN rw0_rd_out[80]
    DIRECTION OUTPUT ;
    USE SIGNAL ;
    SHAPE ABUTMENT ;
    PORT
      LAYER met2 ;
      RECT 164.610 1114.780 164.750 1115.200 ;
    END
  END rw0_rd_out[80]
  PIN rw0_rd_out[81]
    DIRECTION OUTPUT ;
    USE SIGNAL ;
    SHAPE ABUTMENT ;
    PORT
      LAYER met2 ;
      RECT 174.730 1114.780 174.870 1115.200 ;
    END
  END rw0_rd_out[81]
  PIN rw0_rd_out[82]
    DIRECTION OUTPUT ;
    USE SIGNAL ;
    SHAPE ABUTMENT ;
    PORT
      LAYER met2 ;
      RECT 184.850 1114.780 184.990 1115.200 ;
    END
  END rw0_rd_out[82]
  PIN rw0_rd_out[83]
    DIRECTION OUTPUT ;
    USE SIGNAL ;
    SHAPE ABUTMENT ;
    PORT
      LAYER met2 ;
      RECT 194.970 1114.780 195.110 1115.200 ;
    END
  END rw0_rd_out[83]
  PIN rw0_rd_out[84]
    DIRECTION OUTPUT ;
    USE SIGNAL ;
    SHAPE ABUTMENT ;
    PORT
      LAYER met2 ;
      RECT 205.090 1114.780 205.230 1115.200 ;
    END
  END rw0_rd_out[84]
  PIN rw0_rd_out[85]
    DIRECTION OUTPUT ;
    USE SIGNAL ;
    SHAPE ABUTMENT ;
    PORT
      LAYER met2 ;
      RECT 215.210 1114.780 215.350 1115.200 ;
    END
  END rw0_rd_out[85]
  PIN rw0_rd_out[86]
    DIRECTION OUTPUT ;
    USE SIGNAL ;
    SHAPE ABUTMENT ;
    PORT
      LAYER met2 ;
      RECT 225.330 1114.780 225.470 1115.200 ;
    END
  END rw0_rd_out[86]
  PIN rw0_rd_out[87]
    DIRECTION OUTPUT ;
    USE SIGNAL ;
    SHAPE ABUTMENT ;
    PORT
      LAYER met2 ;
      RECT 235.450 1114.780 235.590 1115.200 ;
    END
  END rw0_rd_out[87]
  PIN rw0_rd_out[88]
    DIRECTION OUTPUT ;
    USE SIGNAL ;
    SHAPE ABUTMENT ;
    PORT
      LAYER met2 ;
      RECT 245.570 1114.780 245.710 1115.200 ;
    END
  END rw0_rd_out[88]
  PIN rw0_rd_out[89]
    DIRECTION OUTPUT ;
    USE SIGNAL ;
    SHAPE ABUTMENT ;
    PORT
      LAYER met2 ;
      RECT 255.690 1114.780 255.830 1115.200 ;
    END
  END rw0_rd_out[89]
  PIN rw0_rd_out[90]
    DIRECTION OUTPUT ;
    USE SIGNAL ;
    SHAPE ABUTMENT ;
    PORT
      LAYER met2 ;
      RECT 265.810 1114.780 265.950 1115.200 ;
    END
  END rw0_rd_out[90]
  PIN rw0_rd_out[91]
    DIRECTION OUTPUT ;
    USE SIGNAL ;
    SHAPE ABUTMENT ;
    PORT
      LAYER met2 ;
      RECT 275.930 1114.780 276.070 1115.200 ;
    END
  END rw0_rd_out[91]
  PIN rw0_rd_out[92]
    DIRECTION OUTPUT ;
    USE SIGNAL ;
    SHAPE ABUTMENT ;
    PORT
      LAYER met2 ;
      RECT 286.050 1114.780 286.190 1115.200 ;
    END
  END rw0_rd_out[92]
  PIN rw0_rd_out[93]
    DIRECTION OUTPUT ;
    USE SIGNAL ;
    SHAPE ABUTMENT ;
    PORT
      LAYER met2 ;
      RECT 296.170 1114.780 296.310 1115.200 ;
    END
  END rw0_rd_out[93]
  PIN rw0_rd_out[94]
    DIRECTION OUTPUT ;
    USE SIGNAL ;
    SHAPE ABUTMENT ;
    PORT
      LAYER met2 ;
      RECT 306.290 1114.780 306.430 1115.200 ;
    END
  END rw0_rd_out[94]
  PIN rw0_rd_out[95]
    DIRECTION OUTPUT ;
    USE SIGNAL ;
    SHAPE ABUTMENT ;
    PORT
      LAYER met2 ;
      RECT 316.410 1114.780 316.550 1115.200 ;
    END
  END rw0_rd_out[95]
  PIN rw0_rd_out[96]
    DIRECTION OUTPUT ;
    USE SIGNAL ;
    SHAPE ABUTMENT ;
    PORT
      LAYER met2 ;
      RECT 326.530 1114.780 326.670 1115.200 ;
    END
  END rw0_rd_out[96]
  PIN rw0_rd_out[97]
    DIRECTION OUTPUT ;
    USE SIGNAL ;
    SHAPE ABUTMENT ;
    PORT
      LAYER met2 ;
      RECT 336.650 1114.780 336.790 1115.200 ;
    END
  END rw0_rd_out[97]
  PIN rw0_rd_out[98]
    DIRECTION OUTPUT ;
    USE SIGNAL ;
    SHAPE ABUTMENT ;
    PORT
      LAYER met2 ;
      RECT 346.770 1114.780 346.910 1115.200 ;
    END
  END rw0_rd_out[98]
  PIN rw0_rd_out[99]
    DIRECTION OUTPUT ;
    USE SIGNAL ;
    SHAPE ABUTMENT ;
    PORT
      LAYER met2 ;
      RECT 356.890 1114.780 357.030 1115.200 ;
    END
  END rw0_rd_out[99]
  PIN rw0_rd_out[100]
    DIRECTION OUTPUT ;
    USE SIGNAL ;
    SHAPE ABUTMENT ;
    PORT
      LAYER met2 ;
      RECT 367.010 1114.780 367.150 1115.200 ;
    END
  END rw0_rd_out[100]
  PIN rw0_rd_out[101]
    DIRECTION OUTPUT ;
    USE SIGNAL ;
    SHAPE ABUTMENT ;
    PORT
      LAYER met2 ;
      RECT 377.130 1114.780 377.270 1115.200 ;
    END
  END rw0_rd_out[101]
  PIN rw0_rd_out[102]
    DIRECTION OUTPUT ;
    USE SIGNAL ;
    SHAPE ABUTMENT ;
    PORT
      LAYER met2 ;
      RECT 387.250 1114.780 387.390 1115.200 ;
    END
  END rw0_rd_out[102]
  PIN rw0_rd_out[103]
    DIRECTION OUTPUT ;
    USE SIGNAL ;
    SHAPE ABUTMENT ;
    PORT
      LAYER met2 ;
      RECT 397.370 1114.780 397.510 1115.200 ;
    END
  END rw0_rd_out[103]
  PIN rw0_rd_out[104]
    DIRECTION OUTPUT ;
    USE SIGNAL ;
    SHAPE ABUTMENT ;
    PORT
      LAYER met2 ;
      RECT 407.490 1114.780 407.630 1115.200 ;
    END
  END rw0_rd_out[104]
  PIN rw0_rd_out[105]
    DIRECTION OUTPUT ;
    USE SIGNAL ;
    SHAPE ABUTMENT ;
    PORT
      LAYER met2 ;
      RECT 417.610 1114.780 417.750 1115.200 ;
    END
  END rw0_rd_out[105]
  PIN rw0_rd_out[106]
    DIRECTION OUTPUT ;
    USE SIGNAL ;
    SHAPE ABUTMENT ;
    PORT
      LAYER met2 ;
      RECT 427.730 1114.780 427.870 1115.200 ;
    END
  END rw0_rd_out[106]
  PIN rw0_rd_out[107]
    DIRECTION OUTPUT ;
    USE SIGNAL ;
    SHAPE ABUTMENT ;
    PORT
      LAYER met2 ;
      RECT 437.850 1114.780 437.990 1115.200 ;
    END
  END rw0_rd_out[107]
  PIN rw0_rd_out[108]
    DIRECTION OUTPUT ;
    USE SIGNAL ;
    SHAPE ABUTMENT ;
    PORT
      LAYER met2 ;
      RECT 447.970 1114.780 448.110 1115.200 ;
    END
  END rw0_rd_out[108]
  PIN rw0_rd_out[109]
    DIRECTION OUTPUT ;
    USE SIGNAL ;
    SHAPE ABUTMENT ;
    PORT
      LAYER met2 ;
      RECT 458.090 1114.780 458.230 1115.200 ;
    END
  END rw0_rd_out[109]
  PIN rw0_rd_out[110]
    DIRECTION OUTPUT ;
    USE SIGNAL ;
    SHAPE ABUTMENT ;
    PORT
      LAYER met2 ;
      RECT 468.210 1114.780 468.350 1115.200 ;
    END
  END rw0_rd_out[110]
  PIN rw0_rd_out[111]
    DIRECTION OUTPUT ;
    USE SIGNAL ;
    SHAPE ABUTMENT ;
    PORT
      LAYER met2 ;
      RECT 478.330 1114.780 478.470 1115.200 ;
    END
  END rw0_rd_out[111]
  PIN rw0_rd_out[112]
    DIRECTION OUTPUT ;
    USE SIGNAL ;
    SHAPE ABUTMENT ;
    PORT
      LAYER met2 ;
      RECT 488.450 1114.780 488.590 1115.200 ;
    END
  END rw0_rd_out[112]
  PIN rw0_rd_out[113]
    DIRECTION OUTPUT ;
    USE SIGNAL ;
    SHAPE ABUTMENT ;
    PORT
      LAYER met2 ;
      RECT 498.570 1114.780 498.710 1115.200 ;
    END
  END rw0_rd_out[113]
  PIN rw0_rd_out[114]
    DIRECTION OUTPUT ;
    USE SIGNAL ;
    SHAPE ABUTMENT ;
    PORT
      LAYER met2 ;
      RECT 508.690 1114.780 508.830 1115.200 ;
    END
  END rw0_rd_out[114]
  PIN rw0_rd_out[115]
    DIRECTION OUTPUT ;
    USE SIGNAL ;
    SHAPE ABUTMENT ;
    PORT
      LAYER met2 ;
      RECT 518.810 1114.780 518.950 1115.200 ;
    END
  END rw0_rd_out[115]
  PIN rw0_rd_out[116]
    DIRECTION OUTPUT ;
    USE SIGNAL ;
    SHAPE ABUTMENT ;
    PORT
      LAYER met2 ;
      RECT 528.930 1114.780 529.070 1115.200 ;
    END
  END rw0_rd_out[116]
  PIN rw0_rd_out[117]
    DIRECTION OUTPUT ;
    USE SIGNAL ;
    SHAPE ABUTMENT ;
    PORT
      LAYER met2 ;
      RECT 539.050 1114.780 539.190 1115.200 ;
    END
  END rw0_rd_out[117]
  PIN rw0_rd_out[118]
    DIRECTION OUTPUT ;
    USE SIGNAL ;
    SHAPE ABUTMENT ;
    PORT
      LAYER met2 ;
      RECT 549.170 1114.780 549.310 1115.200 ;
    END
  END rw0_rd_out[118]
  PIN rw0_rd_out[119]
    DIRECTION OUTPUT ;
    USE SIGNAL ;
    SHAPE ABUTMENT ;
    PORT
      LAYER met2 ;
      RECT 559.290 1114.780 559.430 1115.200 ;
    END
  END rw0_rd_out[119]
  PIN rw0_rd_out[120]
    DIRECTION OUTPUT ;
    USE SIGNAL ;
    SHAPE ABUTMENT ;
    PORT
      LAYER met2 ;
      RECT 569.410 1114.780 569.550 1115.200 ;
    END
  END rw0_rd_out[120]
  PIN rw0_rd_out[121]
    DIRECTION OUTPUT ;
    USE SIGNAL ;
    SHAPE ABUTMENT ;
    PORT
      LAYER met2 ;
      RECT 579.530 1114.780 579.670 1115.200 ;
    END
  END rw0_rd_out[121]
  PIN rw0_rd_out[122]
    DIRECTION OUTPUT ;
    USE SIGNAL ;
    SHAPE ABUTMENT ;
    PORT
      LAYER met2 ;
      RECT 589.650 1114.780 589.790 1115.200 ;
    END
  END rw0_rd_out[122]
  PIN rw0_rd_out[123]
    DIRECTION OUTPUT ;
    USE SIGNAL ;
    SHAPE ABUTMENT ;
    PORT
      LAYER met2 ;
      RECT 599.770 1114.780 599.910 1115.200 ;
    END
  END rw0_rd_out[123]
  PIN rw0_rd_out[124]
    DIRECTION OUTPUT ;
    USE SIGNAL ;
    SHAPE ABUTMENT ;
    PORT
      LAYER met2 ;
      RECT 609.890 1114.780 610.030 1115.200 ;
    END
  END rw0_rd_out[124]
  PIN rw0_rd_out[125]
    DIRECTION OUTPUT ;
    USE SIGNAL ;
    SHAPE ABUTMENT ;
    PORT
      LAYER met2 ;
      RECT 620.010 1114.780 620.150 1115.200 ;
    END
  END rw0_rd_out[125]
  PIN rw0_rd_out[126]
    DIRECTION OUTPUT ;
    USE SIGNAL ;
    SHAPE ABUTMENT ;
    PORT
      LAYER met2 ;
      RECT 630.130 1114.780 630.270 1115.200 ;
    END
  END rw0_rd_out[126]
  PIN rw0_rd_out[127]
    DIRECTION OUTPUT ;
    USE SIGNAL ;
    SHAPE ABUTMENT ;
    PORT
      LAYER met2 ;
      RECT 640.250 1114.780 640.390 1115.200 ;
    END
  END rw0_rd_out[127]
  PIN rw0_addr_in[0]
    DIRECTION INPUT ;
    USE SIGNAL ;
    SHAPE ABUTMENT ;
    PORT
      LAYER met3 ;
      RECT 0.000 939.610 0.900 939.910 ;
    END
  END rw0_addr_in[0]
  PIN rw0_addr_in[1]
    DIRECTION INPUT ;
    USE SIGNAL ;
    SHAPE ABUTMENT ;
    PORT
      LAYER met3 ;
      RECT 0.000 968.850 0.900 969.150 ;
    END
  END rw0_addr_in[1]
  PIN rw0_addr_in[2]
    DIRECTION INPUT ;
    USE SIGNAL ;
    SHAPE ABUTMENT ;
    PORT
      LAYER met3 ;
      RECT 0.000 998.090 0.900 998.390 ;
    END
  END rw0_addr_in[2]
  PIN rw0_addr_in[3]
    DIRECTION INPUT ;
    USE SIGNAL ;
    SHAPE ABUTMENT ;
    PORT
      LAYER met3 ;
      RECT 0.000 1027.330 0.900 1027.630 ;
    END
  END rw0_addr_in[3]
  PIN rw0_addr_in[4]
    DIRECTION INPUT ;
    USE SIGNAL ;
    SHAPE ABUTMENT ;
    PORT
      LAYER met3 ;
      RECT 0.000 1056.570 0.900 1056.870 ;
    END
  END rw0_addr_in[4]
  PIN rw0_addr_in[5]
    DIRECTION INPUT ;
    USE SIGNAL ;
    SHAPE ABUTMENT ;
    PORT
      LAYER met3 ;
      RECT 684.040 939.610 684.940 939.910 ;
    END
  END rw0_addr_in[5]
  PIN rw0_addr_in[6]
    DIRECTION INPUT ;
    USE SIGNAL ;
    SHAPE ABUTMENT ;
    PORT
      LAYER met3 ;
      RECT 684.040 968.850 684.940 969.150 ;
    END
  END rw0_addr_in[6]
  PIN rw0_addr_in[7]
    DIRECTION INPUT ;
    USE SIGNAL ;
    SHAPE ABUTMENT ;
    PORT
      LAYER met3 ;
      RECT 684.040 998.090 684.940 998.390 ;
    END
  END rw0_addr_in[7]
  PIN rw0_addr_in[8]
    DIRECTION INPUT ;
    USE SIGNAL ;
    SHAPE ABUTMENT ;
    PORT
      LAYER met3 ;
      RECT 684.040 1027.330 684.940 1027.630 ;
    END
  END rw0_addr_in[8]
  PIN rw0_we_in
    DIRECTION INPUT ;
    USE SIGNAL ;
    SHAPE ABUTMENT ;
    PORT
      LAYER met2 ;
      RECT 650.370 1114.780 650.510 1115.200 ;
    END
  END rw0_we_in
  PIN rw0_ce_in
    DIRECTION INPUT ;
    USE SIGNAL ;
    SHAPE ABUTMENT ;
    PORT
      LAYER met2 ;
      RECT 660.490 1114.780 660.630 1115.200 ;
    END
  END rw0_ce_in
  PIN rw0_clk
    DIRECTION INPUT ;
    USE SIGNAL ;
    SHAPE ABUTMENT ;
    PORT
      LAYER met2 ;
      RECT 670.610 1114.780 670.750 1115.200 ;
    END
  END rw0_clk
  PIN VSS
    DIRECTION INOUT ;
    USE GROUND ;
    PORT
      LAYER met4 ;
      RECT 2.160 4.080 3.360 1111.120 ;
      RECT 13.040 4.080 14.240 1111.120 ;
      RECT 23.920 4.080 25.120 1111.120 ;
      RECT 34.800 4.080 36.000 1111.120 ;
      RECT 45.680 4.080 46.880 1111.120 ;
      RECT 56.560 4.080 57.760 1111.120 ;
      RECT 67.440 4.080 68.640 1111.120 ;
      RECT 78.320 4.080 79.520 1111.120 ;
      RECT 89.200 4.080 90.400 1111.120 ;
      RECT 100.080 4.080 101.280 1111.120 ;
      RECT 110.960 4.080 112.160 1111.120 ;
      RECT 121.840 4.080 123.040 1111.120 ;
      RECT 132.720 4.080 133.920 1111.120 ;
      RECT 143.600 4.080 144.800 1111.120 ;
      RECT 154.480 4.080 155.680 1111.120 ;
      RECT 165.360 4.080 166.560 1111.120 ;
      RECT 176.240 4.080 177.440 1111.120 ;
      RECT 187.120 4.080 188.320 1111.120 ;
      RECT 198.000 4.080 199.200 1111.120 ;
      RECT 208.880 4.080 210.080 1111.120 ;
      RECT 219.760 4.080 220.960 1111.120 ;
      RECT 230.640 4.080 231.840 1111.120 ;
      RECT 241.520 4.080 242.720 1111.120 ;
      RECT 252.400 4.080 253.600 1111.120 ;
      RECT 263.280 4.080 264.480 1111.120 ;
      RECT 274.160 4.080 275.360 1111.120 ;
      RECT 285.040 4.080 286.240 1111.120 ;
      RECT 295.920 4.080 297.120 1111.120 ;
      RECT 306.800 4.080 308.000 1111.120 ;
      RECT 317.680 4.080 318.880 1111.120 ;
      RECT 328.560 4.080 329.760 1111.120 ;
      RECT 339.440 4.080 340.640 1111.120 ;
      RECT 350.320 4.080 351.520 1111.120 ;
      RECT 361.200 4.080 362.400 1111.120 ;
      RECT 372.080 4.080 373.280 1111.120 ;
      RECT 382.960 4.080 384.160 1111.120 ;
      RECT 393.840 4.080 395.040 1111.120 ;
      RECT 404.720 4.080 405.920 1111.120 ;
      RECT 415.600 4.080 416.800 1111.120 ;
      RECT 426.480 4.080 427.680 1111.120 ;
      RECT 437.360 4.080 438.560 1111.120 ;
      RECT 448.240 4.080 449.440 1111.120 ;
      RECT 459.120 4.080 460.320 1111.120 ;
      RECT 470.000 4.080 471.200 1111.120 ;
      RECT 480.880 4.080 482.080 1111.120 ;
      RECT 491.760 4.080 492.960 1111.120 ;
      RECT 502.640 4.080 503.840 1111.120 ;
      RECT 513.520 4.080 514.720 1111.120 ;
      RECT 524.400 4.080 525.600 1111.120 ;
      RECT 535.280 4.080 536.480 1111.120 ;
      RECT 546.160 4.080 547.360 1111.120 ;
      RECT 557.040 4.080 558.240 1111.120 ;
      RECT 567.920 4.080 569.120 1111.120 ;
      RECT 578.800 4.080 580.000 1111.120 ;
      RECT 589.680 4.080 590.880 1111.120 ;
      RECT 600.560 4.080 601.760 1111.120 ;
      RECT 611.440 4.080 612.640 1111.120 ;
      RECT 622.320 4.080 623.520 1111.120 ;
      RECT 633.200 4.080 634.400 1111.120 ;
      RECT 644.080 4.080 645.280 1111.120 ;
      RECT 654.960 4.080 656.160 1111.120 ;
      RECT 665.840 4.080 667.040 1111.120 ;
      RECT 676.720 4.080 677.920 1111.120 ;
    END
  END VSS
  PIN VDD
    DIRECTION INOUT ;
    USE POWER ;
    PORT
      LAYER met4 ;
      RECT 7.600 4.080 8.800 1111.120 ;
      RECT 18.480 4.080 19.680 1111.120 ;
      RECT 29.360 4.080 30.560 1111.120 ;
      RECT 40.240 4.080 41.440 1111.120 ;
      RECT 51.120 4.080 52.320 1111.120 ;
      RECT 62.000 4.080 63.200 1111.120 ;
      RECT 72.880 4.080 74.080 1111.120 ;
      RECT 83.760 4.080 84.960 1111.120 ;
      RECT 94.640 4.080 95.840 1111.120 ;
      RECT 105.520 4.080 106.720 1111.120 ;
      RECT 116.400 4.080 117.600 1111.120 ;
      RECT 127.280 4.080 128.480 1111.120 ;
      RECT 138.160 4.080 139.360 1111.120 ;
      RECT 149.040 4.080 150.240 1111.120 ;
      RECT 159.920 4.080 161.120 1111.120 ;
      RECT 170.800 4.080 172.000 1111.120 ;
      RECT 181.680 4.080 182.880 1111.120 ;
      RECT 192.560 4.080 193.760 1111.120 ;
      RECT 203.440 4.080 204.640 1111.120 ;
      RECT 214.320 4.080 215.520 1111.120 ;
      RECT 225.200 4.080 226.400 1111.120 ;
      RECT 236.080 4.080 237.280 1111.120 ;
      RECT 246.960 4.080 248.160 1111.120 ;
      RECT 257.840 4.080 259.040 1111.120 ;
      RECT 268.720 4.080 269.920 1111.120 ;
      RECT 279.600 4.080 280.800 1111.120 ;
      RECT 290.480 4.080 291.680 1111.120 ;
      RECT 301.360 4.080 302.560 1111.120 ;
      RECT 312.240 4.080 313.440 1111.120 ;
      RECT 323.120 4.080 324.320 1111.120 ;
      RECT 334.000 4.080 335.200 1111.120 ;
      RECT 344.880 4.080 346.080 1111.120 ;
      RECT 355.760 4.080 356.960 1111.120 ;
      RECT 366.640 4.080 367.840 1111.120 ;
      RECT 377.520 4.080 378.720 1111.120 ;
      RECT 388.400 4.080 389.600 1111.120 ;
      RECT 399.280 4.080 400.480 1111.120 ;
      RECT 410.160 4.080 411.360 1111.120 ;
      RECT 421.040 4.080 422.240 1111.120 ;
      RECT 431.920 4.080 433.120 1111.120 ;
      RECT 442.800 4.080 444.000 1111.120 ;
      RECT 453.680 4.080 454.880 1111.120 ;
      RECT 464.560 4.080 465.760 1111.120 ;
      RECT 475.440 4.080 476.640 1111.120 ;
      RECT 486.320 4.080 487.520 1111.120 ;
      RECT 497.200 4.080 498.400 1111.120 ;
      RECT 508.080 4.080 509.280 1111.120 ;
      RECT 518.960 4.080 520.160 1111.120 ;
      RECT 529.840 4.080 531.040 1111.120 ;
      RECT 540.720 4.080 541.920 1111.120 ;
      RECT 551.600 4.080 552.800 1111.120 ;
      RECT 562.480 4.080 563.680 1111.120 ;
      RECT 573.360 4.080 574.560 1111.120 ;
      RECT 584.240 4.080 585.440 1111.120 ;
      RECT 595.120 4.080 596.320 1111.120 ;
      RECT 606.000 4.080 607.200 1111.120 ;
      RECT 616.880 4.080 618.080 1111.120 ;
      RECT 627.760 4.080 628.960 1111.120 ;
      RECT 638.640 4.080 639.840 1111.120 ;
      RECT 649.520 4.080 650.720 1111.120 ;
      RECT 660.400 4.080 661.600 1111.120 ;
      RECT 671.280 4.080 672.480 1111.120 ;
      RECT 682.160 4.080 683.360 1111.120 ;
    END
  END VDD
  OBS
    LAYER met1 ;
    RECT 0 0 684.940 1115.200 ;
    LAYER met2 ;
    RECT 0 0 684.940 1115.200 ;
    LAYER met3 ;
    RECT 0 0 684.940 1115.200 ;
    LAYER met4 ;
    RECT 0 0 684.940 1115.200 ;
  END
END fakeram_512x128

END LIBRARY
